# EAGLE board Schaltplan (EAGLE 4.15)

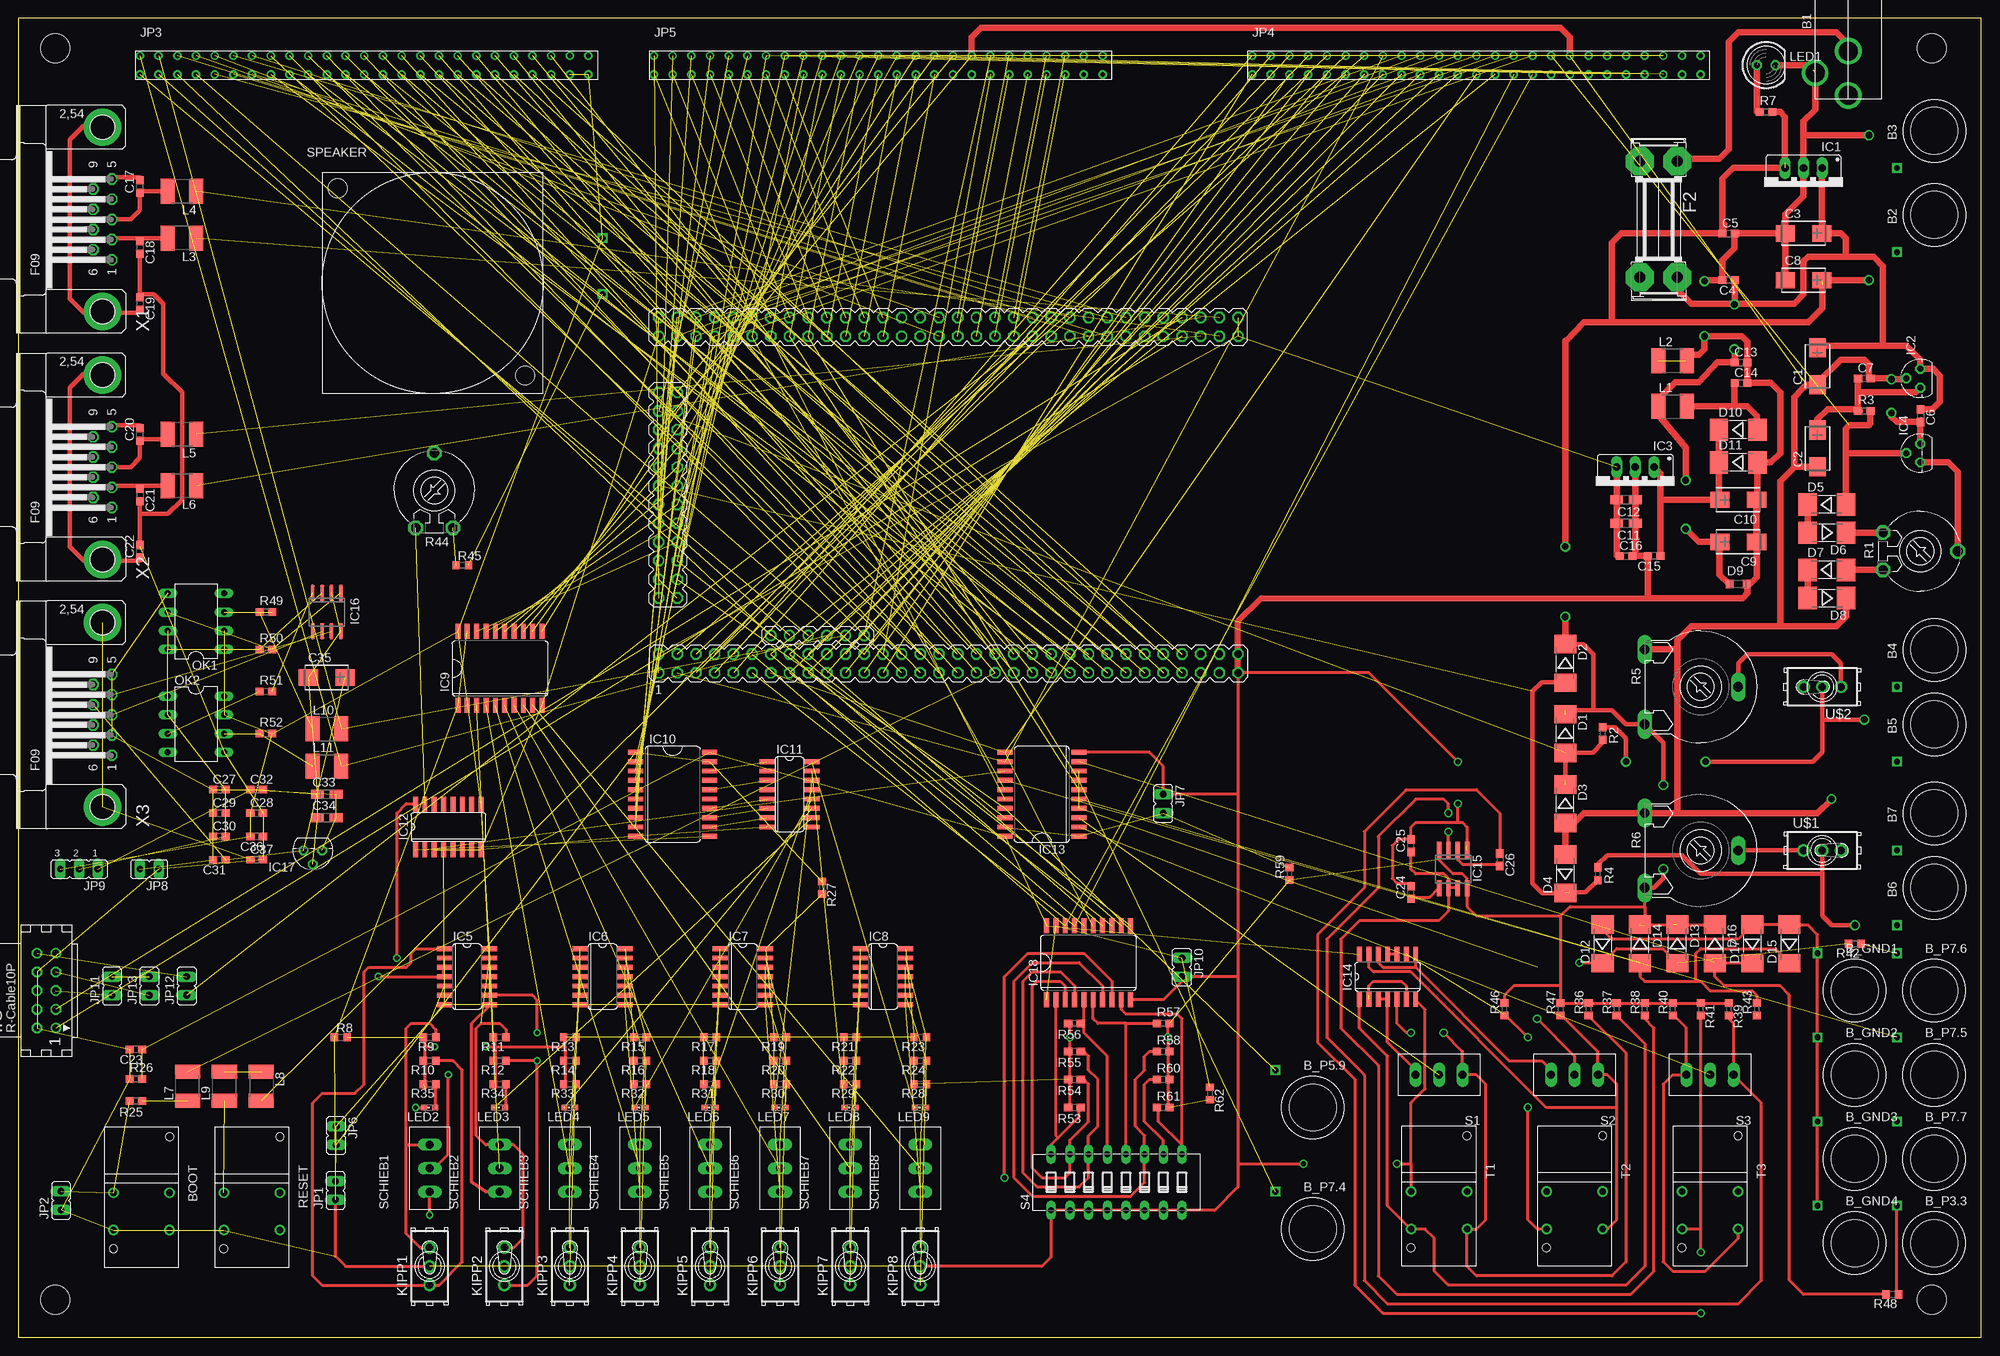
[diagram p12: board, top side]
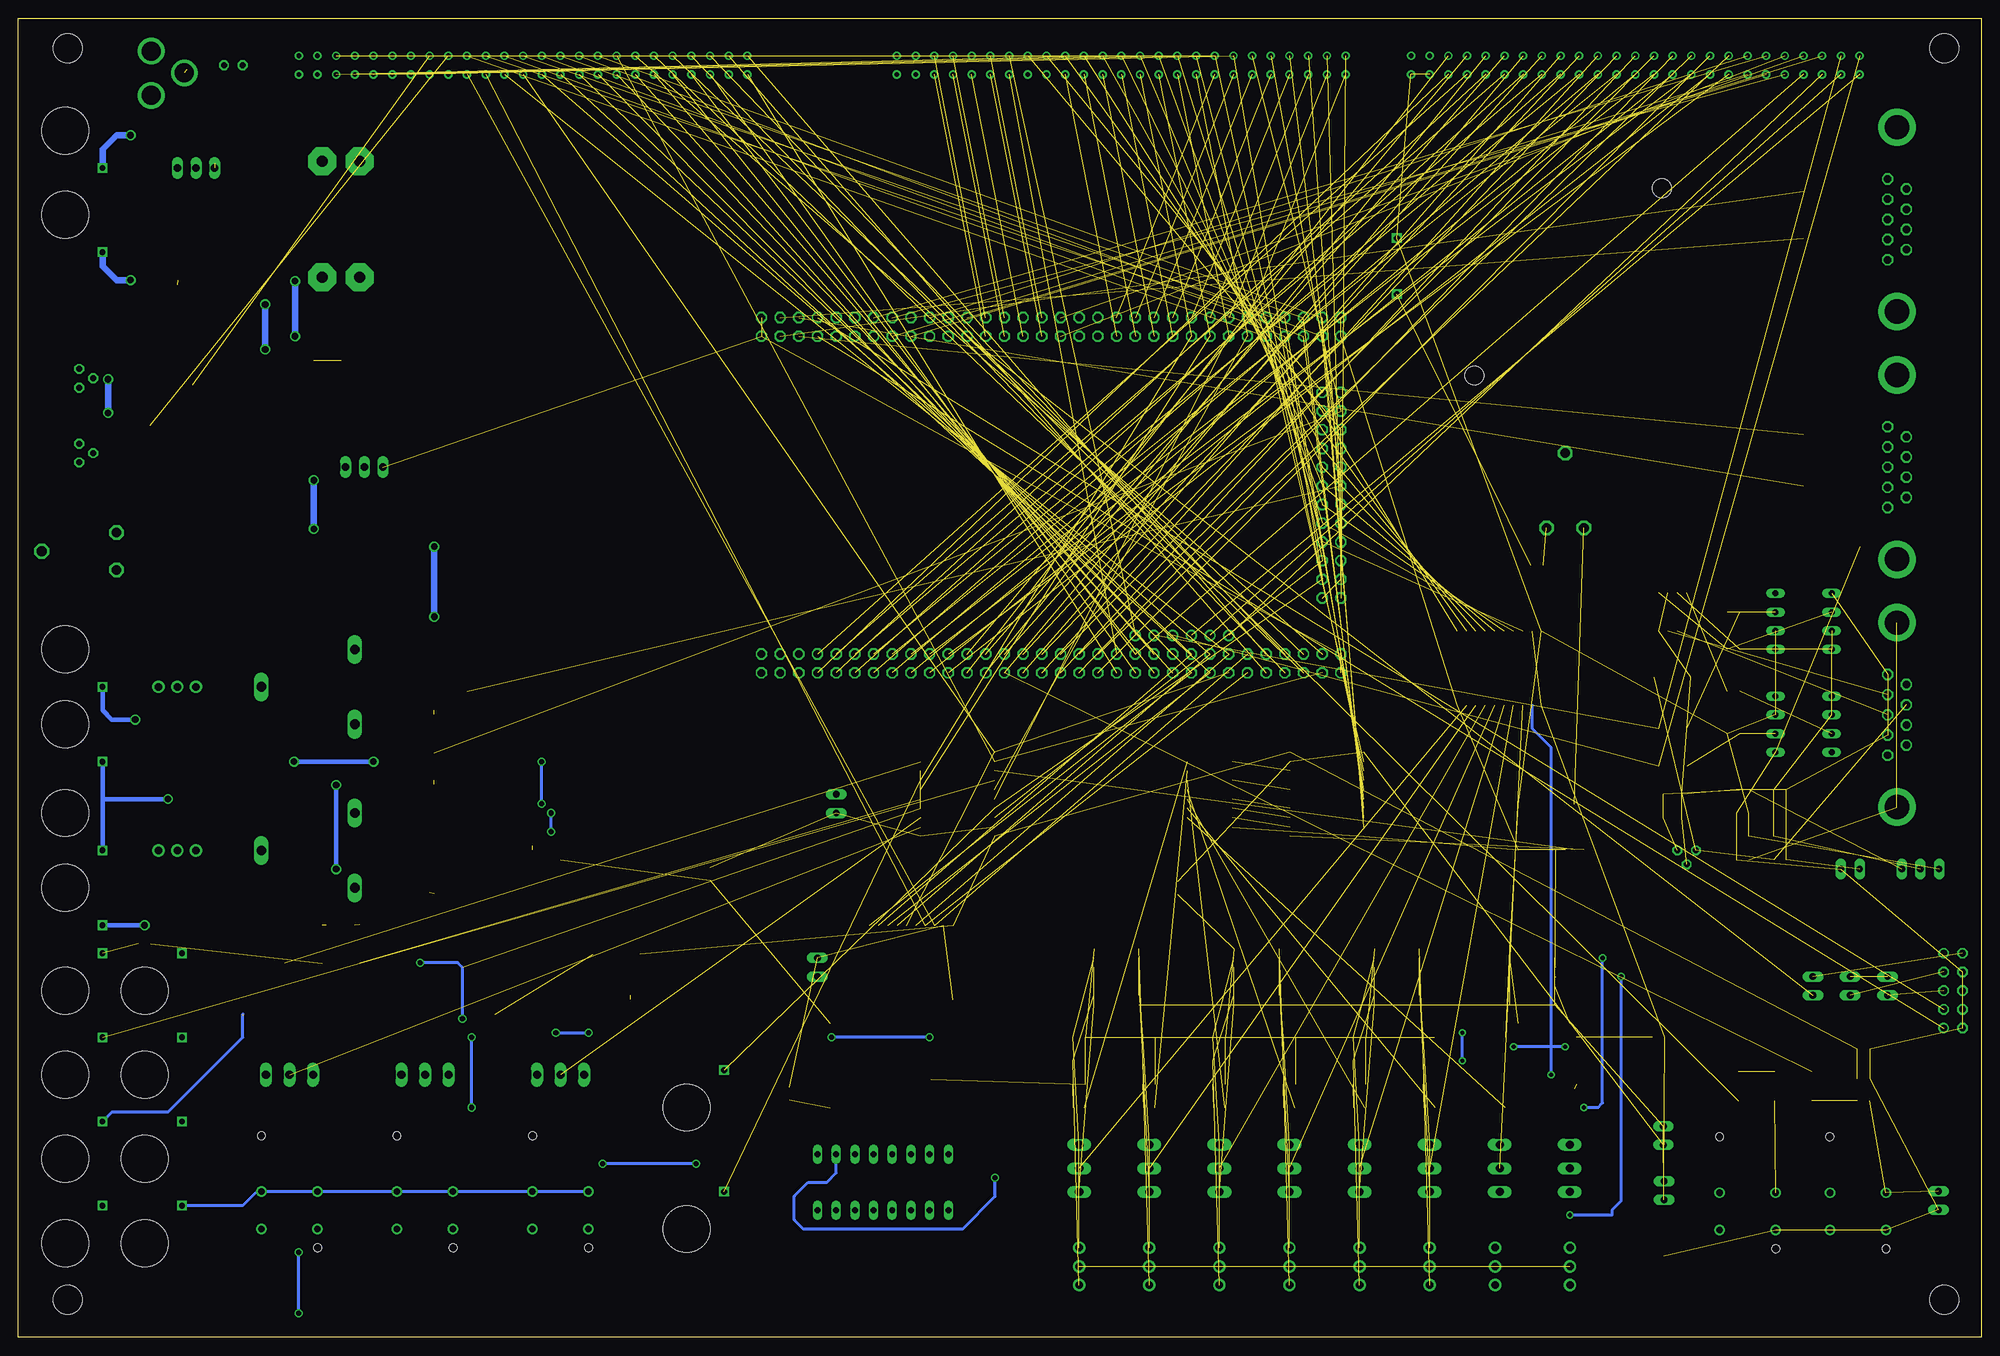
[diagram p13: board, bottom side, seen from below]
Size 266.7 x 179.16 mm. Coordinates in mm from the lower left corner, seen from the top.
Outline: 0.01,0 266.7,0 266.7,179.16 0,179.16 0,100 0.01,100 0.01,0
Copper layers (1*16): Top 0.035mm / dielectric 1.5mm / Bottom 0.035mm
Design rules "default": minimum track width 10mil, minimum drill 24mil, track to track 8mil, track to pad 8mil, pad to pad 8mil, via to via 8mil, smd to smd 8mil, copper to edge 40mil, drill to drill 8mil, minimum pad ring 10mil, minimum via ring 8mil, stop-mask expansion 4mil, vias tented up to drill 0mil, thermal gap 10mil
Holes 4 mm at 5,5.09 5,175.09 260,175.09 260,5.09

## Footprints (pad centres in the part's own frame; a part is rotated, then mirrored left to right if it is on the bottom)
NETZBUCHSE = drill 2.6 round: KONT -13.5,15.5; VCC+ -7.5,15.5; VCC- -10.45,20
BUCHSE01 = drill 0.8 square: 1 -5.08,5.08 | hole 6.4: 0,0
TASTER = drill 0.9 round: 1 2.54,-5.08; 2 -2.54,-5.08; 3 2.54,2.54; 4 -2.54,2.54 | hole 1.1: 5.08,-5.08; -10.16,2.54
CT6032 = smd 2.6 x 2.2: + 2.5,0; - -2.5,0
C0603 = smd 1.1 x 1: 1 -0.85,0; 2 0.85,0
R/2012-12W = smd 1.75 x 1.26: + 1.275,0; - -1.275,0
MELF-MLL41 = smd 2.5 x 3: A 2.625,0; C -2.625,0
SOD110-W = smd 1 x 1.2: A 1.15,0; C -1.15,0
SHK20Q = drill 1.5 pad 3.81 octagon: 1A -7.874,2.54; 1B -7.874,-2.54; 2A 7.874,2.54; 2B 7.874,-2.54
78XXS = drill 1.016 long: GND 0,-2.54; IN -2.54,-2.54; OUT 2.54,-2.54
78LXX = drill 0.813 octagon: GND 0,1.905; IN 1.27,0; OUT -1.27,0
TO92 = drill 0.813 octagon: 1 -1.27,0; 2 0,1.905; 3 1.27,0
SO14 = smd 0.66 x 2.032: 1 -3.81,-3.073; 2 -2.54,-3.073; 3 -1.27,-3.073; 4 0,-3.073; 5 1.27,-3.073; 6 2.54,-3.073; 7 3.81,-3.073; 8 3.81,3.073; 9 2.54,3.073; 10 1.27,3.073; 11 0,3.073; 12 -1.27,3.073; 13 -2.54,3.073; 14 -3.81,3.073
SO20W = smd 0.66 x 2.032: 1 -5.715,-5.029; 2 -4.445,-5.029; 3 -3.175,-5.029; 4 -1.905,-5.029; 5 -0.635,-5.029; 6 0.635,-5.029; 7 1.905,-5.029; 8 3.175,-5.029; 9 4.445,-5.029; 10 5.715,-5.029; 11 5.715,5.029; 12 4.445,5.029; 13 3.175,5.029; 14 1.905,5.029; 15 0.635,5.029; 16 -0.635,5.029; 17 -1.905,5.029; 18 -3.175,5.029; 19 -4.445,5.029; 20 -5.715,5.029
SO16 = smd 0.66 x 2.032: 1 -4.445,-3.073; 2 -3.175,-3.073; 3 -1.905,-3.073; 4 -0.635,-3.073; 5 0.635,-3.073; 6 1.905,-3.073; 7 3.175,-3.073; 8 4.445,-3.073; 9 4.445,3.073; 10 3.175,3.073; 11 1.905,3.073; 12 0.635,3.073; 13 -0.635,3.073; 14 -1.905,3.073; 15 -3.175,3.073; 16 -4.445,3.073
SO08 = smd 0.6 x 2.2: 1 -1.905,-2.6; 2 -0.635,-2.6; 3 0.635,-2.6; 4 1.905,-2.6; 5 1.905,2.6; 6 0.635,2.6; 7 -0.635,2.6; 8 -1.905,2.6
SO8 = smd 0.6 x 2.2: 1 -1.905,-2.6; 2 -0.635,-2.6; 3 0.635,-2.6; 4 1.905,-2.6; 5 1.905,2.6; 6 0.635,2.6; 7 -0.635,2.6; 8 -1.905,2.6
CON10 = drill 0.914 round: 1 -5.08,-1.27 | drill 0.914 octagon: 2 -5.08,1.27; 3 -2.54,-1.27; 4 -2.54,1.27; 5 0,-1.27; 6 0,1.27; 7 2.54,-1.27; 8 2.54,1.27; 9 5.08,-1.27; 10 5.08,1.27
JP1 = drill 0.914 long: 1 0,-1.27; 2 0,1.27
CONN_50POL = drill 0.63 round: P$1 30.48,5.08; P$2 30.48,2.54; P$3 27.94,5.08; P$4 27.94,2.54; P$5 25.4,5.08; P$6 25.4,2.54; P$7 22.86,5.08; P$8 22.86,2.54; P$9 20.32,5.08; P$10 20.32,2.54; P$11 17.78,5.08; P$12 17.78,2.54; P$13 15.24,5.08; P$14 15.24,2.54; P$15 12.7,5.08; P$16 12.7,2.54; P$17 10.16,5.08; P$18 10.16,2.54; P$19 7.62,5.08; P$20 7.62,2.54; P$21 5.08,5.08; P$22 5.08,2.54; P$23 2.54,5.08; P$24 2.54,2.54; P$25 0,5.08; P$26 0,2.54; P$27 -2.54,5.08; P$28 -2.54,2.54; P$29 -5.08,5.08; P$30 -5.08,2.54; P$31 -7.62,5.08; P$32 -7.62,2.54; P$33 -10.16,5.08; P$34 -10.16,2.54; P$35 -12.7,5.08; P$36 -12.7,2.54; P$37 -15.24,5.08; P$38 -15.24,2.54; P$39 -17.78,5.08; P$40 -17.78,2.54; P$41 -20.32,5.08; P$42 -20.32,2.54; P$43 -22.86,5.08; P$44 -22.86,2.54; P$45 -25.4,5.08; P$46 -25.4,2.54; P$47 -27.94,5.08; P$48 -27.94,2.54; P$49 -30.48,5.08; P$50 -30.48,2.54
JP2 = drill 0.914 long: 1 -2.54,0; 2 0,0; 3 2.54,0
ATE1 = drill 1.016 pad 1.676 round: 1 0,-2.54; 2 0,0; 3 0,2.54
L1812 = smd 1.9 x 3.4: 1 -1.95,0; 2 1.95,0
LED5MM = drill 0.813 octagon: A -1.27,0; K 1.27,0
CHIPLED_0603 = smd 0.8 x 0.8: A 0,-0.75; C 0,0.75
MM_GES = drill 1.016 octagon: 1 -24.13,39.37; 2 -21.59,39.37; 3 -24.13,36.83; 4 -21.59,36.83; 5 -24.13,34.29; 6 -21.59,34.29; 7 -24.13,31.75; 8 -21.59,31.75; 9 -24.13,29.21; 10 -21.59,29.21; 11 -24.13,26.67; 12 -21.59,26.67; 13 -24.13,24.13; 14 -21.59,24.13; 15 -24.13,21.59; 16 -21.59,21.59; 17 -24.13,19.05; 18 -21.59,19.05; 19 -24.13,16.51; 20 -21.59,16.51; 21 -24.13,13.97; 22 -21.59,13.97; 23 -24.13,11.43; 24 -21.59,11.43; 25 -24.13,8.89; 26 -21.59,8.89; 27 -24.13,6.35; 28 -21.59,6.35; 29 -24.13,3.81; 30 -21.59,3.81; 31 -24.13,1.27; 32 -21.59,1.27; 33 -24.13,-1.27; 34 -21.59,-1.27; 35 -24.13,-3.81; 36 -21.59,-3.81; 37 -24.13,-6.35; 38 -21.59,-6.35; 39 -24.13,-8.89; 40 -21.59,-8.89; 41 -24.13,-11.43; 42 -21.59,-11.43; 43 -24.13,-13.97; 44 -21.59,-13.97; 45 -24.13,-16.51; 46 -21.59,-16.51; 47 -24.13,-19.05; 48 -21.59,-19.05; 49 -24.13,-21.59; 50 -21.59,-21.59; 51 -24.13,-24.13; 52 -21.59,-24.13; 53 -24.13,-26.67; 54 -21.59,-26.67; 55 -24.13,-29.21; 56 -21.59,-29.21; 57 -24.13,-31.75; 58 -21.59,-31.75; 59 -24.13,-34.29; 60 -21.59,-34.29; 61 -24.13,-36.83; 62 -21.59,-36.83; 63 -24.13,-39.37; 64 -21.59,-39.37; 65 24.13,-39.37; 66 21.59,-39.37; 67 24.13,-36.83; 68 21.59,-36.83; 69 24.13,-34.29; 70 21.59,-34.29; 71 24.13,-31.75; 72 21.59,-31.75; 73 24.13,-29.21; 74 21.59,-29.21; 75 24.13,-26.67; 76 21.59,-26.67; 77 24.13,-24.13; 78 21.59,-24.13; 79 24.13,-21.59; 80 21.59,-21.59; 81 24.13,-19.05; 82 21.59,-19.05; 83 24.13,-16.51; 84 21.59,-16.51; 85 24.13,-13.97; 86 21.59,-13.97; 87 24.13,-11.43; 88 21.59,-11.43; 89 24.13,-8.89; 90 21.59,-8.89; 91 24.13,-6.35; 92 21.59,-6.35; 93 24.13,-3.81; 94 21.59,-3.81; 95 24.13,-1.27; 96 21.59,-1.27; 97 24.13,1.27; 98 21.59,1.27; 99 24.13,3.81; 100 21.59,3.81; 101 24.13,6.35; 102 21.59,6.35; 103 24.13,8.89; 104 21.59,8.89; 105 24.13,11.43; 106 21.59,11.43; 107 24.13,13.97; 108 21.59,13.97; 109 24.13,16.51; 110 21.59,16.51; 111 24.13,19.05; 112 21.59,19.05; 113 24.13,21.59; 114 21.59,21.59; 115 24.13,24.13; 116 21.59,24.13; 117 24.13,26.67; 118 21.59,26.67; 119 24.13,29.21; 120 21.59,29.21; 121 24.13,31.75; 122 21.59,31.75; 123 24.13,34.29; 124 21.59,34.29; 125 24.13,36.83; 126 21.59,36.83; 127 24.13,39.37; 128 21.59,39.37; 129 13.97,39.37; 130 13.97,36.83; 131 11.43,39.37; 132 11.43,36.83; 133 8.89,39.37; 134 8.89,36.83; 135 6.35,39.37; 136 6.35,36.83; 137 3.81,39.37; 138 3.81,36.83; 139 1.27,39.37; 140 1.27,36.83; 141 -1.27,39.37; 142 -1.27,36.83; 143 -3.81,39.37; 144 -3.81,36.83; 145 -6.35,39.37; 146 -6.35,36.83; 147 -8.89,39.37; 148 -8.89,36.83; 149 -11.43,39.37; 150 -11.43,36.83; 151 -13.97,39.37; 152 -13.97,36.83 | drill 1.016 round: 153 -19.05,24.13; 154 -19.05,21.59; 155 -19.05,19.05; 156 -19.05,16.51; 157 -19.05,13.97; 158 -19.05,11.43
DIL08 = drill 0.813 long: 1 -3.81,-3.81; 2 -1.27,-3.81; 3 1.27,-3.81; 4 3.81,-3.81; 5 3.81,3.81; 6 1.27,3.81; 7 -1.27,3.81; 8 -3.81,3.81
LI10 = drill 1.321 octagon: A -2.54,-5.08; E 2.54,-5.08; S 0,5.08
R0603 = smd 1.1 x 1: 1 -0.85,0; 2 0.85,0
LI15 = drill 1.321 long: A -5.08,-7.62; E 5.08,-7.62; S 0,5.08
R0603' = smd 1 x 1.1: 1 -0.85,0; 2 0.85,0
SCHIEBESCHALTER = drill 1.1 long: P$1 -3.2,0; P$2 0,0; P$3 3.2,0
DIP08YL = drill 0.813 long: 1 -8.89,-3.81; 2 -6.35,-3.81; 3 -3.81,-3.81; 4 -1.27,-3.81; 5 1.27,-3.81; 6 3.81,-3.81; 7 6.35,-3.81; 8 8.89,-3.81; 9 8.89,3.81; 10 6.35,3.81; 11 3.81,3.81; 12 1.27,3.81; 13 -1.27,3.81; 14 -3.81,3.81; 15 -6.35,3.81; 16 -8.89,3.81
LAUTSPRECHER = drill 0.8 square: + 38.1,-8.89; - 38.1,-16.51 | hole 2.6: 2.12,-2.12; 27.56,-27.56
F09HP = drill 1.016 octagon: 1 -5.486,-1.27; 2 -2.743,-1.27; 3 0,-1.27; 4 2.743,-1.27; 5 5.486,-1.27; 6 -4.115,1.27; 7 -1.372,1.27; 8 1.372,1.27; 9 4.115,1.27 | drill 3.302 pad 5.08 round: G1 -12.522,0; G2 12.522,0

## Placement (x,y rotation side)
B1  NETZBUCHSE  [NETZBUCHSE]  264.16,182.21 90 top
B2  BUCHSE01  [BUCHSE01]  260.35,152.49 90 top
B3  BUCHSE01  [BUCHSE01]  260.35,163.92 90 top
B4  BUCHSE01  [BUCHSE01]  260.35,93.43 90 top
B5  BUCHSE01  [BUCHSE01]  260.35,83.27 90 top
B6  BUCHSE01  [BUCHSE01]  260.35,61.05 90 top
B7  BUCHSE01  [BUCHSE01]  260.35,71.21 90 top
B_GND1  BUCHSE01  [BUCHSE01]  249.56,47.08 0 top
B_GND2  BUCHSE01  [BUCHSE01]  249.56,35.65 0 top
B_GND3  BUCHSE01  [BUCHSE01]  249.56,24.22 0 top
B_GND4  BUCHSE01  [BUCHSE01]  249.56,12.79 0 top
B_P3.3  BUCHSE01  [BUCHSE01]  260.35,12.79 0 top
B_P5.9  Buchse P5.9  [BUCHSE01]  175.9,31.2 0 top
B_P7.4  BUCHSE01  [BUCHSE01]  175.9,14.69 0 top
B_P7.5  BUCHSE01  [BUCHSE01]  260.35,35.65 0 top
B_P7.6  BUCHSE01  [BUCHSE01]  260.35,47.08 0 top
B_P7.7  BUCHSE01  [BUCHSE01]  260.35,24.22 0 top
BOOT  TASTER  [TASTER]  18,17.09 270 top
C1  1µ  [CT6032]  244.47,131.91 90 top
C2  1µ  [CT6032]  244.47,120.74 90 top
C3  100µ  [CT6032]  242.57,149.95 0 top
C4  10n  [C0603]  232.41,143.6 180 top
C5  10n  [C0603]  232.41,149.95 0 top
C6  1n  [C0603]  258.44,125.18 270 top
C7  1n  [C0603]  250.82,130.26 0 top
C8  100µ  [CT6032]  242.57,143.6 0 top
C9  10µ  [CT6032]  233.68,108.04 180 top
C10  10µ  [CT6032]  233.68,113.75 180 top
C11  4,7µ  [R/2012-12W]  218.44,110.58 180 top
C12  4,7µ  [R/2012-12W]  218.44,113.75 180 top
C13  100n  [C0603]  234.06,132.42 0 top
C14  100n  [C0603]  234.06,129.63 0 top
C15  100n  [C0603]  222.25,106.13 180 top
C16  100n  [C0603]  218.44,106.13 0 top
C17  22p  [C0603]  16.51,156.3 90 top
C18  22p  [C0603]  16.51,148.04 270 top
C19  100n  [C0603]  16.51,140.42 270 top
C20  22pF  [C0603]  16.51,122.64 90 top
C21  22pF  [C0603]  16.51,114.39 270 top
C22  100nF  [C0603]  16.51,106.77 90 top
C23  100n  [C0603]  16,39.09 180 top
C24  10nF  [C0603]  189.23,60.41 90 top
C25  10nF  [C0603]  189.23,66.76 90 top
C26  1uF  [C0603]  201.29,64.86 270 top
C27  100n  [C0603]  27.3,74.38 0 top
C28  100n  [C0603]  32.38,71.21 0 top
C29  100n  [C0603]  27.3,71.21 0 top
C30  100n  [C0603]  27.3,68.03 0 top
C31  100n  [C0603]  27.3,64.86 180 top
C32  100n  [C0603]  32.38,74.38 0 top
C33  4u7/6  [R/2012-12W]  41.91,73.75 0 top
C34  4u7/6  [R/2012-12W]  41.91,70.57 0 top
C35  10u/25  [CT6032]  41.91,89.62 0 top
C36  100n  [C0603]  32.38,68.03 180 top
C37  100n  [C0603]  32.38,64.86 0 top
D1  1N4001  [MELF-MLL41]  210.19,82 270 top
D2  1N4001  [MELF-MLL41]  210.19,91.53 270 top
D3  1N4001  [MELF-MLL41]  210.19,72.48 270 top
D4  1N4001  [MELF-MLL41]  210.19,62.95 90 top
D5  1N4148  [MELF-MLL41]  245.75,113.12 0 top
D6  1N4148  [MELF-MLL41]  245.75,109.31 180 top
D7  1N4148  [MELF-MLL41]  245.75,104.23 0 top
D8  1N4148  [MELF-MLL41]  245.75,100.42 180 top
D9  [SOD110-W]  233.68,102.32 0 top
D10  4001  [MELF-MLL41]  233.68,123.28 0 top
D11  4001  [MELF-MLL41]  233.68,118.83 0 top
D12  1N4001  [MELF-MLL41]  215.26,53.43 90 top
D13  1N4001  [MELF-MLL41]  225.43,53.43 270 top
D14  1N4001  [MELF-MLL41]  220.34,53.43 270 top
D15  1N4001  [MELF-MLL41]  240.66,53.43 90 top
D16  1N4001  [MELF-MLL41]  230.5,53.43 270 top
D17  1N4001  [MELF-MLL41]  235.59,53.43 90 top
F2  [SHK20Q]  222.88,151.85 270 top
IC1  7805T  [78XXS]  242.57,156.3 180 top
IC2  [78LXX]  258.44,130.26 90 top
IC3  7805T  [78XXS]  219.71,115.66 180 top
IC4  7805L  [TO92]  258.44,120.1 90 top
IC5  74S00D  [SO14]  60.96,48.98 270 top
IC6  74S00D  [SO14]  79.38,48.98 270 top
IC7  74S00D  [SO14]  98.42,48.98 270 top
IC8  74S00D  [SO14]  117.47,48.98 270 top
IC9  74LS541DW  [SO20W]  65.44,90.85 0 top
IC10  74LS541DW  [SO20W]  88.9,73.75 270 top
IC11  ULN2003AD  [SO16]  104.78,73.75 270 top
IC12  ULN2003AD  [SO16]  58.42,69.3 0 top
IC13  74LS541DW  [SO20W]  139.06,73.75 90 top
IC14  74S00D  [SO14]  186.06,48.98 0 top
IC15  NE555D  [SO08]  194.94,63.59 180 top
IC16  PCA82C250T/N4  [SO8]  41.91,98.51 180 top
IC17  78L05  [TO92]  40.01,66.13 180 top
IC18  74LS541DW  [SO20W]  145.41,50.89 0 top
IIC  [CON10]  3.81,47.08 90 top
JP1  [JP1]  43.09,19.93 0 top
JP2  [JP1]  5.79,18.55 0 top
JP3  CONN_50POL  [CONN_50POL]  46.99,169 0 top
JP4  CONN_50POL  [CONN_50POL]  198.12,169 0 top
JP5  CONN_50POL  [CONN_50POL]  116.84,169 0 top
JP6  [JP1]  43.18,27.39 180 top
JP7  [JP1]  155.57,72.48 180 top
JP8  [JP1]  17.78,63.59 90 top
JP9  [JP2]  8.26,63.59 180 top
JP10  [JP1]  158.12,50.25 180 top
JP11  [JP1]  12.7,47.71 0 top
JP12  [JP1]  22.86,47.71 0 top
JP13  [JP1]  17.78,47.71 0 top
KIPP1  ATE1  [ATE1]  55.88,9.61 0 top
KIPP2  ATE1  [ATE1]  66.04,9.61 0 top
KIPP3  ATE1  [ATE1]  74.93,9.61 0 top
KIPP4  ATE1  [ATE1]  84.45,9.61 0 top
KIPP5  ATE1  [ATE1]  93.98,9.61 0 top
KIPP6  ATE1  [ATE1]  103.5,9.61 0 top
KIPP7  ATE1  [ATE1]  113.03,9.61 0 top
KIPP8  ATE1  [ATE1]  122.56,9.61 0 top
L1  2,2µ  [L1812]  224.79,126.45 0 top
L2  2,2µ  [L1812]  224.79,132.68 0 top
L3  2u2  [L1812]  22.23,149.31 180 top
L4  2u2  [L1812]  22.23,155.66 180 top
L5  2u2  [L1812]  22.23,122.64 180 top
L6  2u2  [L1812]  22.23,115.66 180 top
L7  2u2  [L1812]  23,34.09 90 top
L8  2u2  [L1812]  33,34.09 270 top
L9  2u2  [L1812]  28,34.09 90 top
L10  2u2  [L1812]  41.91,82.64 0 top
L11  2u2  [L1812]  41.91,77.56 0 top
LED1  [LED5MM]  237.49,172.81 0 top
LED2  [CHIPLED_0603]  55.88,31.2 90 top
LED3  [CHIPLED_0603]  65.41,31.2 90 top
LED4  [CHIPLED_0603]  74.93,31.2 90 top
LED5  [CHIPLED_0603]  84.45,31.2 90 top
LED6  [CHIPLED_0603]  93.98,31.2 90 top
LED7  [CHIPLED_0603]  103.5,31.2 90 top
LED8  [CHIPLED_0603]  113.03,31.2 90 top
LED9  [CHIPLED_0603]  122.56,31.2 90 top
MM_C1  [MM_GES]  126.36,114.39 90 top
OK1  6N137  [DIL08]  24.13,97.24 90 top
OK2  6N137  [DIL08]  24.13,83.27 270 top
R1  [LI10]  258.44,106.77 270 top
R2  1000  [R0603]  215.26,82 270 top
R3  2k  [R0603]  250.82,125.82 0 top
R4  1000  [R0603]  214.63,62.95 270 top
R5  [LI15]  228.6,88.35 270 top
R6  [LI15]  228.6,66.13 270 top
R7  56R  [R0603]  237.49,166.46 0 top
R8  10k  [R0603']  43.81,40.73 0 top
R9  3.3k  [R0603']  55.88,40.73 180 top
R10  3.3k  [R0603']  55.88,37.55 180 top
R11  3.3k  [R0603']  65.41,40.73 180 top
R12  3.3k  [R0603']  65.41,37.55 180 top
R13  3.3k  [R0603']  74.93,40.73 180 top
R14  3.3k  [R0603']  74.93,37.55 180 top
R15  3.3k  [R0603']  84.45,40.73 180 top
R16  3.3k  [R0603']  84.45,37.55 180 top
R17  3.3k  [R0603']  93.98,40.73 180 top
R18  3.3k  [R0603']  93.98,37.55 180 top
R19  3.3k  [R0603']  103.5,40.73 180 top
R20  3.3k  [R0603']  103.5,37.55 180 top
R21  3.3k  [R0603']  113.03,40.73 180 top
R22  3.3k  [R0603']  113.03,37.55 180 top
R23  3.3k  [R0603']  122.56,40.73 180 top
R24  3.3k  [R0603']  122.56,37.55 180 top
R25  10k  [R0603]  16,32.09 180 top
R26  4k7  [R0603]  16,35.09 0 top
R27  10k  [R0603']  109.22,61.05 270 top
R28  220R  [R0603']  122.56,34.38 180 top
R29  220R  [R0603']  113.03,34.38 180 top
R30  220R  [R0603']  103.5,34.38 180 top
R31  220R  [R0603']  93.98,34.38 180 top
R32  220R  [R0603']  84.45,34.38 180 top
R33  220R  [R0603']  74.93,34.38 180 top
R34  220R  [R0603']  65.41,34.38 180 top
R35  220R  [R0603']  55.88,34.38 180 top
R36  3.3k  [R0603']  213.36,44.54 90 top
R37  3.3k  [R0603']  217.17,44.54 90 top
R38  9,1k  [R0603']  220.98,44.54 90 top
R39  2,2k  [R0603']  232.41,44.54 270 top
R40  3,3k  [R0603']  224.79,44.54 90 top
R41  3,3k  [R0603']  228.6,44.54 270 top
R42  1K  [R0603']  249.56,53.43 180 top
R43  1k  [R0603']  236.22,44.54 90 top
R44  [LI10]  56.52,115.02 0 top
R45  27R  [R0603']  60.33,104.86 0 top
R46  3.3k  [R0603']  201.93,44.54 90 top
R47  3.3k  [R0603']  209.55,44.54 90 top
R48  1K  [R0603']  254.63,5.8 180 top
R49  390R  [R0603]  33.66,98.51 0 top
R50  390R  [R0603]  33.66,93.43 0 top
R51  390R  [R0603]  33.66,87.72 0 top
R52  390R  [R0603]  33.66,82 0 top
R53  3.3k  [R0603]  143.51,31.2 180 top
R54  3.3k  [R0603]  143.51,35.01 180 top
R55  3.3k  [R0603]  143.51,38.82 180 top
R56  3.3k  [R0603]  143.51,42.63 180 top
R57  3.3k  [R0603]  155.57,42.63 0 top
R58  3.3k  [R0603]  155.57,38.82 0 top
R59  10K  [R0603']  172.72,62.95 90 top
R60  3.3k  [R0603]  155.57,35.01 0 top
R61  3.3k  [R0603]  155.57,31.2 0 top
R62  [R0603']  161.93,33.11 270 top
RESET  TASTER  [TASTER]  33,17.09 270 top
S1  SCHIEBESCHALTER_WECHSLER  [SCHIEBESCHALTER]  193.04,35.65 180 top
S2  SCHIEBESCHALTER_WECHSLER  [SCHIEBESCHALTER]  211.46,35.65 180 top
S3  SCHIEBESCHALTER_WECHSLER  [SCHIEBESCHALTER]  229.87,35.65 180 top
S4  [DIP08YL]  149.22,21.04 0 top
SCHIEB1  SCHIEBESCHALTER_WECHSLER  [SCHIEBESCHALTER]  55.9,22.95 90 top
SCHIEB2  SCHIEBESCHALTER_WECHSLER  [SCHIEBESCHALTER]  65.41,22.95 90 top
SCHIEB3  SCHIEBESCHALTER_WECHSLER  [SCHIEBESCHALTER]  74.93,22.95 90 top
SCHIEB4  SCHIEBESCHALTER_WECHSLER  [SCHIEBESCHALTER]  84.45,22.95 90 top
SCHIEB5  SCHIEBESCHALTER_WECHSLER  [SCHIEBESCHALTER]  93.98,22.95 90 top
SCHIEB6  SCHIEBESCHALTER_WECHSLER  [SCHIEBESCHALTER]  103.5,22.95 90 top
SCHIEB7  SCHIEBESCHALTER_WECHSLER  [SCHIEBESCHALTER]  113.03,22.95 90 top
SCHIEB8  SCHIEBESCHALTER_WECHSLER  [SCHIEBESCHALTER]  122.56,22.95 90 top
SPEAKER  LAUTSPRECHER  [LAUTSPRECHER]  41.27,158.2 0 top
T1  TASTER  [TASTER]  194.31,17.23 270 top
T2  TASTER  [TASTER]  212.72,17.23 270 top
T3  TASTER  [TASTER]  231.14,17.23 270 top
U$1  ATE1  [ATE1]  245.11,66.13 270 top
U$2  ATE1  [ATE1]  245.11,88.35 90 top
X1  [F09HP]  11.43,151.85 90 top
X2  [F09HP]  11.43,118.2 90 top
X3  RS-485  [F09HP]  11.43,84.54 90 top

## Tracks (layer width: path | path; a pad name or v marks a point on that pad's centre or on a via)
/IRTC  (1 unrouted)
/NMI  (1 unrouted)
/RD  (1 unrouted)
/RDY  (1 unrouted)
/RES  (1 unrouted)
/RESI  (1 unrouted)
/RESO  (1 unrouted)
/WR  (1 unrouted)
A0  (1 unrouted)
A1  (1 unrouted)
A2  (1 unrouted)
A3  (1 unrouted)
A4  (1 unrouted)
A5  (1 unrouted)
A6  (1 unrouted)
A7  (1 unrouted)
A8  (1 unrouted)
A9  (1 unrouted)
A10  (1 unrouted)
A11  (1 unrouted)
A12  (1 unrouted)
A13  (1 unrouted)
A14  (1 unrouted)
A15  (1 unrouted)
A16  (1 unrouted)
A17  (1 unrouted)
A18  (1 unrouted)
A19  (1 unrouted)
A20  (1 unrouted)
A21  (2 unrouted)
A22  (2 unrouted)
A23  (1 unrouted)
ALE  (1 unrouted)
B4  (via drill 0.9)
  Top 0.61: 245.11,83.91 U$2.2 | 245.11,83.91 v250.82,83.91 | R2.1 216.96,82.85 218.44,81.37 v218.44,78.19 | v229.24,78.19 243.84,78.19 245.11,79.46 245.11,83.91
  Bottom 0.61: v250.82,83.91 254,83.91 255.27,85.18 B4.1 | v218.44,78.19 v229.24,78.19
BUCHSE  (via drill 0.9)
  Top 0.61: 245.11,62.95 245.11,57.24 246.38,55.97 v249.56,55.97 | 245.11,62.95 U$1.2 | R4.1 214.63,64.22 215.9,65.49 226.06,65.49 228.6,62.95 245.11,62.95
  Bottom 0.61: v249.56,55.97 B6.1
BUCHSEP3.3  (1 unrouted)
  Top 0.406: D17.C 235.5,50.89 230.5,50.89 D16.A 230.5,48.98 231.78,47.71 239.4,47.71 240.66,46.44 240.66,7.71 242.57,5.8 R48.2 254,5.8
CAN5V  (8 unrouted)
CANGND  (14 unrouted)
CCIN2  (1 unrouted)
CCOUT2  (1 unrouted)
D0  (1 unrouted)
D1  (1 unrouted)
D2  (1 unrouted)
D3  (1 unrouted)
D4  (2 unrouted)
D5  (1 unrouted)
D6  (1 unrouted)
D7  (1 unrouted)
D8  (1 unrouted)
D9  (1 unrouted)
D10  (1 unrouted)
D11  (1 unrouted)
D12  (1 unrouted)
D13  (1 unrouted)
D14  (1 unrouted)
D15  (1 unrouted)
GND  (via drill 0.7, 0.9)  (41 unrouted)
  Top 0.406: B_GND4.1 B_GND3.1 B_GND2.1 B_GND1.1 244.47,54.7 243.21,55.97 240.66,55.97 D15.A 235.67,56.05 235.59,55.97 | 189.23,23.58 T1.2 | 189.23,23.58 189.23,31.84 191.13,33.74 191.13,44.54 189.87,45.81 IC14.7 | D12.A 215.26,55.33 216.53,54.06 233.68,54.06 235.59,55.97 | 235.59,55.97 D17.A | C24.2 189.23,61.68 187.32,61.68 186.69,62.32 186.69,66.76 187.54,67.61 C25.2 189.23,69.3 189.87,69.94 195.58,69.94 | 195.58,69.94 196.22,69.94 196.85,69.3 196.85,66.76 | 221.4,100.42 221.62,101.05 | v195.58,78.19 183.51,90.26 MM_C1.63 165.74,73.75 | 195.58,69.94 v195.58,72.48 | 165.74,73.75 165.74,48.98 | 165.74,23.58 v174.62,23.58 | v187.32,23.58 189.23,23.58 | 165.74,48.98 165.74,23.58 | 165.74,23.58 165.74,20.41 162.56,17.23 S4.8 S4.7 S4.6 S4.5 S4.4 S4.3 S4.2 S4.1 140.34,10.88 139.06,9.61 KIPP8.2 | IC18.10 155.63,45.86 158.12,48.35 JP10.2 165.74,48.98 | IC13.10 153.67,79.46 155.57,77.56 JP7.1 165.74,73.75 | JP1.1 43.09,10.97 44.45,9.61 KIPP1.2
  Top 0.61: 16.51,141.06 C19.1 16.51,141.69 | 16.51,141.69 C18.2 | 16.51,107.4 C22.2 16.51,111.85 | 16.51,111.85 C21.2 | 16.51,141.69 18.41,141.69 19.68,140.42 19.68,130.9 22.23,128.36 22.23,113.75 20.32,111.85 16.51,111.85
  Top 0.813: 221.4,100.42 168.91,100.42 165.74,97.24 MM_C1.64 MM_C1.63
  Top 0.864: C12.- IC3.GND | C12.- | C11.- C12.- | 219.71,106.13 C16.2 | C11.- | 219.71,106.13 C11.- | 219.71,106.13 C15.2 221.4,100.42 234.31,100.42 234.95,101.05 234.95,102.32
  Top 0.914: C3.- 240.07,143.64 240.03,143.6 | 240.03,143.6 C8.- | 240.03,143.6 239.81,143.81 | C3.- 240.07,152.53 242.57,155.03 IC1.GND 242.57,163.28 | B1.VCC- 244.16,166.78 242.57,165.19 242.57,163.28 | LED1.K 243.21,172.81 243.84,172.17 | 242.57,163.28 v251.46,163.28 | 233.43,149.95 C3.- | C9.- 236.18,107.44 236.22,107.4 236.85,108.04 | C9.- C10.- 236.22,113.75 236.31,113.84 D11.A 238.12,118.83 239.4,120.1 239.4,128.36 238.12,129.63 C14.2 234.91,131.95 234.7,132.17 234.91,132.38 C13.2 234.91,135.26 234.19,135.98 v229.11,135.98 229.11,134.2 228.35,133.44 227.33,133.44 226.57,132.68 L2.2 | C9.- 236.22,108.04 236.22,103.21 235.33,102.32 234.95,102.32 D9.A | v229.11,143.47 229.24,143.6 C4.2 231.56,146.31 233.17,147.92 233.17,149.69 233.43,149.95 | 233.43,149.95 C5.2
  Bottom 0.406: T1.2 T1.4 T2.2 T2.4 T3.2 T3.4 234.31,19.77 236.22,17.87 B_GND4.1 | v195.58,72.48 v195.58,78.19 | v174.62,23.58 v187.32,23.58
  Bottom 0.914: B3.1 255.27,161.38 253.37,163.28 v251.46,163.28 | v229.11,135.98 v229.11,143.47
N  (1 unrouted)
N$3
  Top 0.914: R1.S 263.52,117.56 262.25,118.83 IC4.1
N$4
  Top 0.61: R6.S U$1.1
N$5
  Top 0.406: S1.P$3 189.84,36.31 186.06,40.09 IC14.4 184.89,45.91 184.78,45.81 IC14.3
N$6
  Top 0.914: D6.C R1.A
N$7
  Top 0.914: D7.A R1.E
N$8
  Top 0.914: 249.97,126.03 249.97,128.36 | 249.97,128.36 C7.1 | 249.97,126.03 250.19,125.82 R3.1 249.97,126.03 | IC2.OUT 257.81,128.36 249.97,128.36 | C2.+ 244.47,124.68 245.87,126.07 249.94,126.07 249.97,126.03
N$9
  Top 0.914: D6.A 243.21,109.31 243.12,109.39 D5.C
N$10
  Top 0.61: R5.S 233.68,91.53 234.95,92.8 246.38,92.8 247.65,91.53 U$2.1
N$11
  Top 0.914: D10.A 236.22,125.18 234.95,126.45 233.17,126.45 | L1.2 233.17,126.45 | C14.1 233.17,129.59 233.17,126.45
N$12
  Top 0.864: C15.1 223.1,117.35 | 223.1,117.35 IC3.IN | 223.1,117.35 223.1,113.75 231.14,113.75
  Top 0.914: C10.+ 231.14,113.75 231.06,113.84 D11.C 231.14,118.83 231.06,118.92 D10.C
N$13
  Top 0.914: D8.A 243.21,100.42 243.12,100.5 D7.C
N$14
  Top 0.61: C22.1 16.51,105.5 11.61,105.5 X2.G1 11.43,105.5 8.89,105.5 6.99,107.4 6.99,128.99 8.89,130.9 11.25,130.9 X2.G2
N$15
  Top 0.914: R7.1 236.22,166.46 LED1.A
N$16
  Top 0.61: C20.2 16.51,123.91 12.93,123.91 X2.5
N$17
  Top 0.914: B1.VCC+ 248.66,175.61 247.01,177.25 233.68,177.25 232.41,175.98 232.41,161.38 231.14,160.11 226.69,160.11 226.31,159.73 F2.1A
N$18
  Top 0.61: C19.2 16.09,139.15 11.43,139.15 | X1.G2 11.25,164.55 8.89,164.55 6.99,162.65 6.99,141.06 8.89,139.15 11.43,139.15 | 11.43,139.15 X1.G1
N$19
  Top 0.61: X1.2 12.9,149.31 16.51,149.31 | 16.51,149.31 C18.1 | 16.51,149.31 L3.2
N$20
  Top 0.61: C17.2 16.51,157.57 12.93,157.57 X1.5
N$21
  Top 0.61: X1.3 15.24,151.85 16.51,153.12 C17.1 16.51,155.66 L4.2
N$22
  Top 0.406: R10.1 59.05,37.55 60.33,36.28 60.33,10.25 57.15,7.07 KIPP1.1 41.27,7.07 40.01,8.34 40.01,31.84 41.27,33.11 45.72,33.11 46.99,34.38 46.99,49.62 47.62,50.25 52.7,50.25 53.34,50.89 53.34,52.16 53.98,52.79 IC5.1
N$23  (via drill 0.6)  (2 unrouted)
  Top 0.406: SCHIEB1.P$1 55.9,16.61 v55.88,16.6 | v48.9,48.98 57.78,48.98 57.78,50.25
  Bottom 0.406: v55.88,16.6 50.16,16.6 50.16,17.23 48.9,18.5 v48.9,48.98
N$24  (1 unrouted)
  Top 0.406: KIPP1.3 54.61,12.15 52.7,14.06 52.7,26.12 | SCHIEB1.P$3 55.88,26.12 52.7,26.12 | R9.1 56.73,41.78 55.88,42.63 53.34,42.63 52.7,42 52.7,26.12
N$25  (1 unrouted)
N$26  (via drill 0.6)
  Top 0.406: KIPP2.1 69.22,7.07 70.48,8.34 v70.48,37.55 R12.1 | IC5.9 69.85,46.44 70.48,45.81 v70.48,41.36
  Bottom 0.406: v70.48,37.55 v70.48,41.36
N$27  (1 unrouted)
  Top 0.406: KIPP2.3 67.31,12.15 68.58,13.42 68.58,24.85 67.31,26.12 65.41,26.12 | R11.1 66.25,41.78 65.41,42.63 62.87,42.63 62.23,42 62.23,27.39 63.5,26.12 65.41,26.12 | 65.41,26.12 SCHIEB2.P$3
N$28  (1 unrouted)
  Top 0.406: SCHIEB2.P$1 63.52,19.75 61.59,21.04 61.59,42.63 64.14,45.17 IC5.8
N$29  (1 unrouted)
N$30  (2 unrouted)
N$31  (3 unrouted)
N$32  (2 unrouted)
N$33  (1 unrouted)
N$34  (1 unrouted)
N$35  (2 unrouted)
N$36  (3 unrouted)
N$37  (2 unrouted)
N$38  (1 unrouted)
N$39  (2 unrouted)
N$40  (3 unrouted)
N$41  (2 unrouted)
N$42  (1 unrouted)
N$43  (2 unrouted)
N$44  (3 unrouted)
N$45  (2 unrouted)
N$46  (1 unrouted)
N$47  (2 unrouted)
N$48  (3 unrouted)
N$49  (2 unrouted)
N$50  (1 unrouted)
N$53  (2 unrouted)
N$54  (3 unrouted)
N$55  (2 unrouted)
N$56  (1 unrouted)
N$57  (via drill 0.6)  (1 unrouted)
  Top 0.406: SCHIEB1.P$2 56.52,22.95 58.42,24.85 v58.42,35.65
  Bottom 0.406: v58.42,35.65 58.42,80.1 60.96,82.64 60.96,85.81
N$58  (1 unrouted)
N$59  (1 unrouted)
N$60  (1 unrouted)
N$61  (1 unrouted)
N$62  (1 unrouted)
N$63  (1 unrouted)
N$64  (1 unrouted)
N$65  (3 unrouted)
N$66  (2 unrouted)
N$67  (1 unrouted)
N$68  (1 unrouted)
N$69  (1 unrouted)
  Top 0.406: IC14.6 188.59,47.71 187.96,48.35 184.15,48.35 183.51,47.71 183.51,46.44
N$70  (3 unrouted)
N$71  (1 unrouted)
N$73  (1 unrouted)
N$75  (1 unrouted)
N$76  (1 unrouted)
N$77  (1 unrouted)
N$78  (1 unrouted)
N$79
  Top 0.406: IC14.1 182.25,42 186.06,38.19 186.06,17.87 T1.1 191.13,14.69 192.41,13.42 192.41,8.98 194.31,7.07 218.44,7.07 220.98,9.61 220.98,39.88 R37.1
N$80
  Top 0.406: LED2.A 56.52,31.2 56.73,31.42 R35.1
N$81
  Top 0.406: LED3.A 66.04,31.2 66.25,31.42 R34.1
N$82  (1 unrouted)
N$83  (1 unrouted)
N$84  (1 unrouted)
N$85  (1 unrouted)
N$86  (1 unrouted)
N$87  (1 unrouted)
N$88  (via drill 0.6)
  Top 0.406: v53.98,31.2 LED2.C | v51.44,51.52 51.44,71.21 52.7,72.48 53.98,72.48 IC12.16
  Bottom 0.406: v51.44,51.52 51.44,31.84 52.07,31.2 v53.98,31.2
N$89  (1 unrouted)
N$90  (1 unrouted)
N$91  (1 unrouted)
N$94  (1 unrouted)
N$95  (1 unrouted)
N$96  (1 unrouted)
N$97  (1 unrouted)
N$98  (1 unrouted)
N$103
  Top 0.406: IC15.5 192.98,60.99 191.77,59.78 189.23,59.78 C24.1
N$104
  Top 0.406: R38.1 220.98,43.27 222.25,42 222.25,8.98 219.07,5.8 187.32,5.8 184.78,8.34 184.78,36.92 179.71,42 179.71,54.06 182.25,56.6 193.04,56.6 194.31,57.87 IC15.6 194.31,61.05 | IC15.7 195.58,61.05 194.31,61.05 | 194.31,61.05 194.31,62.32 193.68,62.95 189.87,62.95 189.23,63.59 C25.1 189.23,66.13
N$105  (via drill 0.7)
  Top 0.406: R39.2 232.41,43.27 233.07,42.61 S3.P$1 233.04,35.65 236.85,31.84 236.85,7.71 233.68,4.53 186.06,4.53 182.88,7.71 182.88,35.65 177.8,40.73 177.8,54.06 184.78,61.05 184.78,68.03 189.87,73.11 193.68,73.11 194.31,72.48 v194.31,71.21 | IC15.3 v194.31,68.67
  Bottom 0.406: v194.31,68.67 v194.31,71.21
N$106  (1 unrouted)
N$107
  Top 0.406: IC15.2 195.58,64.86 196.22,64.22 201.29,64.22 C26.2
N$108  (via drill 0.7)
  Top 0.406: 228.6,14.69 T3.1 | 228.6,43.9 R41.2 228.6,14.69 | C26.1 201.29,71.21 198.12,74.38 188.59,74.38 182.88,68.67 182.88,61.05 176.53,54.7 176.53,40.09 181.61,35.01 181.61,7.07 185.42,3.26 v228.6,3.26 | v228.6,11.52 228.6,14.69
  Bottom 0.406: v228.6,3.26 v228.6,11.52
N$109  (via drill 0.7)  (3 unrouted)
  Top 0.406: D13.A 223.44,52.79 217.17,52.79 215.26,50.89 | S2.P$2 211.46,38.19 v206.38,43.27 | 215.26,50.89 D12.C | v212.09,50.89 215.26,50.89
  Bottom 0.406: v212.09,50.89 207.01,50.89 206.38,50.25 v206.38,43.27
N$110  (1 unrouted)
  Top 0.406: D15.C 240.66,50.89 238.76,52.79 228.6,52.79 227.97,52.16 227.97,48.35 | 227.97,48.35 220.98,48.35 220.34,48.98 D14.A 220.34,50.89 | R43.2 236.22,46.44 235.59,47.08 229.87,47.08 228.6,48.35 227.97,48.35
N$111  (1 unrouted)
  Bottom 0.406: B_P7.7.1 254,30.57 246.38,30.57 236.22,40.73 236.22,43.9
N$112
  Top 0.406: T3.3 233.68,13.42 229.24,8.98 224.79,8.98 223.52,10.25 223.52,34.38 224.79,35.65 S3.P$3 | S3.P$3 226.69,35.65 | R40.1 224.79,43.9 226.67,42.02 S3.P$3
N$113  (1 unrouted)
N$114  (1 unrouted)
N$115
  Top 0.406: S2.P$3 208.25,36.31 207.01,37.55 202.56,37.55 189.87,50.25 | 189.87,52.16 IC14.8 189.87,50.25 | 189.87,50.25 185.42,50.25 184.78,50.89 IC14.12 184.78,52.16
N$116
  Top 0.406: IC14.10 187.32,52.16 187.22,52.06 IC14.11
N$117
  Top 0.406: T2.3 215.9,14.69 217.17,15.96 217.17,31.2 | 217.17,31.2 217.17,34.38 215.9,35.65 S2.P$1 | S2.P$1 214.63,35.65 | R47.1 209.55,43.9 214.66,38.8 S2.P$1 | IC14.13 183.51,50.25 184.15,49.62 189.23,49.62 207.65,31.2 217.17,31.2
N$118  (via drill 0.7)
  Top 0.406: S1.P$1 196.22,35.65 | S1.P$1 198.12,35.65 199.39,34.38 199.39,15.96 198.12,14.69 T1.3 196.85,9.61 198.12,8.34 216.53,8.34 218.44,10.25 218.44,38.61 R36.1 | S1.P$1 196.24,38.8 v193.68,41.36 | v189.23,41.36 188.59,41.36 187.32,42.63 IC14.5
  Bottom 0.406: v193.68,41.36 v189.23,41.36
N$119  (3 unrouted)
N$120  (via drill 0.7)  (1 unrouted)
  Top 0.406: T2.1 206.38,14.69 205.1,15.96 v205.1,31.2 | R46.1 201.93,43.9 v205.1,40.73
  Bottom 0.406: v205.1,31.2 v205.1,40.73
N$121  (1 unrouted)
N$122
  Top 0.406: R48.1 255.27,5.8 B_P3.3.1
N$123  (4 unrouted)
N$124  (3 unrouted)
N$125  (1 unrouted)
N$126  (2 unrouted)
N$127  (1 unrouted)
N$128  (1 unrouted)
N$129  (1 unrouted)
N$130  (2 unrouted)
N$131  (1 unrouted)
N$132  (2 unrouted)
N$133  (1 unrouted)
N$134
  Top 0.406: S4.16 140.34,26.12 141.29,27.08 | R53.1 144.15,31.2 144.15,29.93 141.29,27.08 | 141.29,27.08 140.97,27.39 IC18.2
N$135
  Top 0.406: R54.1 144.78,35.01 145.41,34.38 145.41,29.3 142.88,26.76 S4.15 142.88,22.31 142.24,21.68 139.06,21.68 137.79,22.95 137.79,47.71 138.43,48.35 141.6,48.35 142.24,47.71 IC18.3
N$136
  Top 0.406: R55.1 144.78,38.82 145.41,38.19 145.41,36.28 146.69,35.01 146.69,28.66 145.41,27.39 S4.14 145.41,21.68 144.15,20.41 138.43,20.41 136.53,22.31 136.53,48.35 137.79,49.62 141.6,49.62 143.51,47.71 IC18.4
N$137
  Top 0.406: S4.13 147.96,38.19 144.78,41.36 144.78,42 | R56.1 144.78,42.63 144.78,42 | 144.78,42 IC18.5
N$138
  Top 0.406: S4.12 150.5,42.63 | 154.94,42.63 R57.1 150.5,42.63 | IC18.6 146.05,43.27 146.69,42.63 150.5,42.63
N$139
  Top 0.406: 154.94,38.82 R58.1 153.67,38.82 153.03,38.19 153.03,36.28 151.76,35.01 151.76,28.66 153.03,27.39 S4.11 153.03,21.04 151.13,19.14 137.79,19.14 135.25,21.68 135.25,48.35 137.79,50.89 144.15,50.89 147.32,47.71 IC18.7
N$140  (via drill 0.7)
  Top 0.406: S4.10 155.57,26.76 153.03,29.3 153.03,34.38 153.67,35.01 R60.1 154.94,35.01 | IC18.8 148.59,48.35 144.78,52.16 137.16,52.16 133.99,48.98 v133.99,21.68
  Bottom 0.406: v133.99,21.68 133.99,19.14 138.43,14.69 160.02,14.69 161.29,15.96 161.29,19.14 159.38,21.04 156.84,21.04 155.57,22.31 S4.10
N$141
  Top 0.406: R61.1 154.94,31.2 154.94,29.3 158.12,26.12 S4.9 158.12,43.27 157.48,43.9 150.5,43.9 149.86,44.54 IC18.9
N$144  (3 unrouted)
N$145  (1 unrouted)
N$146  (1 unrouted)
N$147  (1 unrouted)
NETZ  (via drill 0.9)
  Top 0.914: IC1.IN 245.07,158.8 C3.+ 247.65,149.95 248.28,149.31 248.28,146.77 | 248.28,146.77 243.21,146.77 242.57,146.14 242.57,141.69 241.3,140.42 233.17,140.42 | 233.17,140.42 233.04,140.42 | 253.37,134.71 253.37,145.5 252.09,146.77 248.28,146.77 | D9.C 232.41,102.32 231.14,103.59 231.14,108.04 C9.+ 228.35,108.04 v226.57,109.82 | v226.57,116.42 226.57,120.87 223.01,125.06 223.01,126.07 222.84,126.25 L1.1 222.84,127.42 225.17,129.76 228.35,129.76 230.89,132.42 C13.1 233.21,134.16 v233.17,134.2 | C6.1 258.53,126.03 258.57,126.07 260.1,126.07 261.11,127.09 261.11,130.65 260.22,131.53 IC2.IN 258.44,132.8 256.54,134.71 253.37,134.71 | C1.+ 244.47,134.58 244.35,134.71 253.37,134.71 | v233.17,140.3 233.17,140.42 | C4.1 233.26,140.64 233.04,140.42 | 233.04,140.42 227.33,140.42 225.43,142.33 F2.2A
  Bottom 0.914: v226.57,109.82 v226.57,116.42 | v233.17,134.2 v233.17,140.3
P2.0  (2 unrouted)
P2.1  (2 unrouted)
P2.2  (2 unrouted)
P2.3  (2 unrouted)
P2.4  (2 unrouted)
P2.5  (2 unrouted)
P2.6  (2 unrouted)
P2.7  (2 unrouted)
P2.8  (2 unrouted)
P2.9  (1 unrouted)
P2.10  (1 unrouted)
P2.11  (1 unrouted)
P2.12  (1 unrouted)
P2.13  (1 unrouted)
P2.14  (1 unrouted)
P2.15  (1 unrouted)
P3.0  (2 unrouted)
P3.1  (2 unrouted)
P3.2  (2 unrouted)
P3.3  (3 unrouted)
P3.4  (2 unrouted)
P3.5  (2 unrouted)
P3.6  (2 unrouted)
P3.7  (2 unrouted)
P3.8  (1 unrouted)
P3.9  (1 unrouted)
P3.10  (1 unrouted)
P3.11  (1 unrouted)
P3.12  (2 unrouted)
P3.13  (1 unrouted)
P3.15  (1 unrouted)
P5.0  (3 unrouted)
P5.1  (3 unrouted)
P5.2  (3 unrouted)
P5.3  (3 unrouted)
P5.4  (3 unrouted)
P5.5  (3 unrouted)
P5.6  (3 unrouted)
P5.7  (3 unrouted)
P5.8  (3 unrouted)
P5.9  (4 unrouted)
P5.10  (3 unrouted)
  Top 0.61: 210.19,75.65 D1.A 213.91,79.38 215.26,80.73 R2.2
P5.11  (1 unrouted)
P5.12  (3 unrouted)
  Top 0.61: R4.2 212.94,60.41 210.82,60.41 | D4.C 207.09,60.33 205.74,61.68 205.74,87.72 207.01,88.99 210.19,88.99 D2.A
P5.13  (1 unrouted)
P5.14  (1 unrouted)
P5.15  (1 unrouted)
P6.0  (1 unrouted)
P6.1  (1 unrouted)
P6.2  (1 unrouted)
P6.3  (1 unrouted)
P6.5  (1 unrouted)
P6.6  (1 unrouted)
P6.7  (1 unrouted)
P7.0  (1 unrouted)
P7.1  (1 unrouted)
P7.2  (1 unrouted)
P7.3  (1 unrouted)
P7.4  (3 unrouted)
P7.5  (2 unrouted)
P7.6  (2 unrouted)
P7.7  (2 unrouted)
P8.0  (1 unrouted)
P8.1  (1 unrouted)
P8.2  (1 unrouted)
P8.3  (1 unrouted)
P8.4  (1 unrouted)
P8.5  (1 unrouted)
P8.6  (1 unrouted)
P8.7  (1 unrouted)
RI1  (1 unrouted)
RI2  (1 unrouted)
RXD
  Top 0.61: L5.2 19.64,122.01 16.51,122.01 | X2.3 15.24,118.2 16.51,119.47 16.51,122.01 | 16.51,122.01 C20.1
SCL  (1 unrouted)
SDA  (1 unrouted)
TO1  (1 unrouted)
TO2  (1 unrouted)
TXD
  Top 0.61: X2.2 12.9,115.66 16.51,115.66 | 16.51,115.66 C21.1 | 16.51,115.66 L6.2
VAGND  (via drill 0.9)  (7 unrouted)
  Top 0.864: 239.4,96.61 227.33,96.61 225.43,94.7 225.43,93.43 | 225.43,71.21 225.43,93.43 | 225.43,71.21 244.47,71.21 v246.38,73.11 | 210.19,65.49 D4.A D3.A 211.37,69.85 212.72,71.21 R6.A 225.43,71.21 | 225.43,93.43 R5.A | JP4.P$15 210.82,176.62 209.55,177.89 130.81,177.89 129.54,176.62 JP5.P$15
  Top 0.914: C6.2 IC4.3 | C6.2 258.44,124.42 258.57,124.55 | C6.2 255.23,124.33 254.51,125.06 v254.51,125.56 | IC2.GND 256.54,130.14 v254.51,130.14 | v254.51,130.14 254.38,130.26 | 244.47,118.2 C2.- 241.34,118.24 241.3,118.2 | v254.51,130.14 254.63,130.26 C7.2 251.46,130.26 251.46,132.17 250.82,132.8 247.65,132.8 244.47,129.63 C1.- 242.99,129.41 242.57,128.99 | 242.57,128.99 241.94,128.36 | D8.C 248.37,97.96 247.01,96.61 239.4,96.61 239.4,116.29 241.3,118.2 | 241.3,118.2 241.3,127.72 242.57,128.99
  Bottom 0.61: 255.27,72.48 255.27,73.11 v246.38,73.11 | 255.27,72.48 B7.1 | 255.27,72.48 B5.1
  Bottom 0.914: v254.51,130.14 v254.51,125.56
VAREF  (3 unrouted)
  Top 0.914: R3.2 251.68,124.13 251.46,123.91 248.79,123.91 248.28,123.41 248.28,119.98 | D5.A 248.28,113.12 248.28,119.98 | 248.28,119.98 248.41,119.98 248.54,120.1 IC4.2
VCC  (5 unrouted)
VCC1  (4 unrouted)
  Top 0.864: C12.+ IC3.OUT | C12.+ | C11.+ C12.+ | C16.1 217.17,106.13 C11.+ | C11.+
VCC2  (via drill 0.6, 0.7, 0.9)  (43 unrouted)
  Top 0.406: 220.98,58.51 220.98,55.97 | 220.98,58.51 R6.E | D14.C 224.79,56.05 | 224.79,56.05 225.97,56.05 226.06,55.97 | 224.79,56.05 224.79,55.97 224.88,56.05 D16.C | R39.1 228.81,45.39 228.6,45.17 R41.1 225,45.39 224.79,45.17 R40.2 221.19,45.39 220.98,45.17 R38.2 217.38,45.39 217.17,45.17 R37.2 213.57,45.39 213.36,45.17 R36.2 R47.2 | R47.2 209.13,45.39 | 209.55,47.71 R47.2 | 209.55,57.24 209.55,47.71 | 209.55,57.24 210.82,58.51 220.98,58.51 | R46.2 201.93,46.44 203.2,47.71 209.55,47.71 | IC15.4 193.04,64.86 194.94,62.95 196.22,62.95 196.85,62.32 IC15.8 196.85,58.51 198.12,57.24 209.55,57.24 | R53.2 142.88,31.42 142.88,35.01 R54.2 142.88,35.23 142.88,38.82 R55.2 142.88,39.04 v142.88,40.73 | v142.88,40.73 142.88,42.63 R56.2 142.88,42.42 v142.88,40.73 | v156.21,40.73 156.21,38.82 | v156.21,40.73 156.21,42.42 R57.2 156.21,42.63 v156.21,40.73 | 156.21,38.82 R58.2 | 156.21,38.82 156.21,35.01 R60.2 156.21,34.8 156.21,31.2 R61.2 | 55.24,37.55 55.03,37.77 | 55.24,33.74 55.24,37.55 | R9.2 55.24,40.73 55.24,39.46 | 55.24,37.55 R10.2 | 55.24,37.55 55.24,39.46 | R11.2 64.77,40.73 64.77,39.46 | 64.77,37.55 R12.2 | 64.77,39.46 64.77,37.55 | R34.2 64.77,34.38 64.77,37.55 | 74.3,37.55 R14.2 | 74.3,39.46 74.3,37.55 | R33.2 74.3,34.38 74.3,37.55 | R13.2 74.3,40.73 74.3,39.46 | 64.77,39.46 74.3,39.46 | 55.24,39.46 v56.52,39.46 | v63.5,39.46 64.77,39.46
  Top 0.61: 214,85.18 210.19,85.18 | 214,85.18 216.53,85.18 218.44,83.27 R5.E 223.52,80.73 v223.52,75.02 | D2.C 212.64,94.15 214,92.8 214,85.18 | R6.E 222.25,61.05 223.52,62.32 v223.52,63.59
  Top 0.864: D2.C v210.19,97.88 | 210.19,135.28 210.19,135.34 | 210.19,135.28 210.25,135.28 | v210.19,107.4 210.19,135.28
  Top 0.914: R7.2 239.4,166.46 240.03,165.82 240.03,159.47 | C5.1 231.56,157.35 233.04,158.84 IC1.OUT | C8.+ v251.46,143.6 | C5.1 231.78,151.22 | C5.1 217.81,149.95 216.53,148.68 216.53,137.88 | D2.C 210.19,94.07 | 210.19,135.22 210.25,135.28 212.72,137.88 216.53,137.88 | 216.53,137.88 243.21,137.88 245.11,139.79 245.11,142.96
  Bottom 0.406: v142.88,40.73 v156.21,40.73 | v56.52,39.46 v63.5,39.46
  Bottom 0.61: v223.52,63.59 v223.52,75.02
  Bottom 0.864: v210.19,97.88 v210.19,107.4
  Bottom 0.914: v251.46,143.6 253.37,143.6 255.27,145.5 B2.1
VCC3  (1 unrouted)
